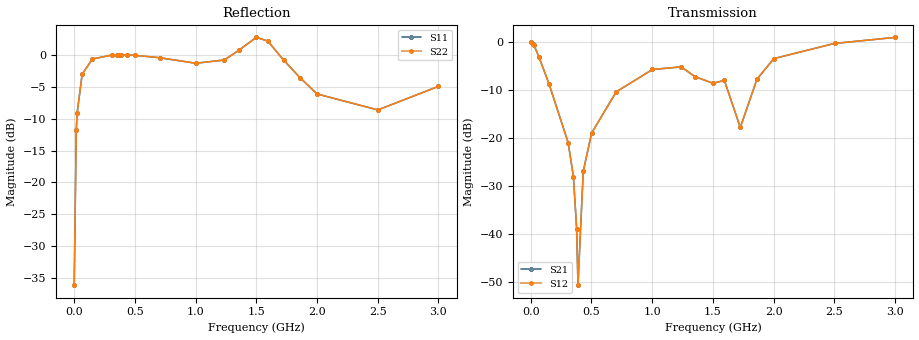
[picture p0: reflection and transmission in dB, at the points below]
!s-Parameter Generated by FASTRON Sdn. Bhd.
!FASTRON P/N : MICC-R27X
!Keysight Technologies,E4991B,MY54100416,A.01.15
!Date: Fri Aug 21 15:37:45 2026
!Version  : Rev00 Fri Aug 21 15:37:45 2026
!Data & Calibration Information:
!PortZ  Port1:50+j0  Port2:50+j0
!When reading, reference impedance value at option line is always used.
!Remarks : This data is being provided solely for informational purposes.
!Freq	S11	S21	S12	S22
# Hz S dB R 50
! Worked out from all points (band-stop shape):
!   1601 points, 1 MHz to 3 GHz, reference 50 ohm
!   highest |S21| = 0.92 dB at 3 GHz (marker M1); lowest = -50.6 dB at 389 MHz (marker M2)
!   |S21| within 3 dB of the highest: start of sweep to 51.23 MHz; 2.117 GHz to end of sweep
!   lowest |S11| = -36.1 dB at 1 MHz (marker M3), VSWR 1.03, Z = 50.2 + j1.57 ohm
!   |S11| at or under -10 dB: start of sweep to 22.54 MHz
!   |S22| runs from -36.1 to 2.8 dB; largest |S21 - S12| = 0
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1000000  -36.07 83.3  -0.01 -0.9  -0.01 -0.9  -36.07 83.3
1.786938e7  -11.82 73.6  -0.36 -14.9  -0.36 -14.9  -11.82 73.6
2.536688e7  -9.09 68.2  -0.64 -20.6  -0.64 -20.6  -9.09 68.2
6.660312e7  -3.05 44.4  -3.10 -44.8  -3.10 -44.8  -3.05 44.4
1.5095e8  -0.66 21.3  -8.79 -68.0  -8.79 -68.0  -0.66 21.3
3.083975e8  -0.06 5.1  -21.02 -83.1  -21.02 -83.1  -0.06 5.1
3.515081e8  -0.03 2.2  -28.13 -83.8  -28.13 -83.8  -0.03 2.2
3.777494e8  -0.03 0.6  -38.85 -75.0  -38.85 -75.0  -0.03 0.6
3.889956e8  -0.02 -0.0  -50.63 14.6  -50.63 14.6  -0.02 -0.0
4.321062e8  -0.03 -2.6  -26.97 83.9  -26.97 83.9  -0.03 -2.6
5.014581e8  -0.09 -6.5  -18.98 81.8  -18.98 81.8  -0.09 -6.5
7.038906e8  -0.46 -17.5  -10.41 71.5  -10.41 71.5  -0.46 -17.5
1.001916e9  -1.33 -31.0  -5.76 59.1  -5.76 59.1  -1.33 -31.0
1.238088e9  -0.82 -32.9  -5.22 64.5  -5.22 64.5  -0.82 -32.9
1.354299e9  0.67 -23.6  -7.27 88.6  -7.27 88.6  0.67 -23.6
1.5005e9  2.72 2.4  -8.63 -171.1  -8.63 -171.1  2.72 2.4
1.594219e9  2.15 14.2  -8.03 -127.6  -8.03 -127.6  2.15 14.2
1.725425e9  -0.84 5.4  -17.83 -41.5  -17.83 -41.5  -0.84 5.4
1.862254e9  -3.63 -15.8  -7.79 26.1  -7.79 26.1  -3.63 -15.8
2.000958e9  -6.14 -36.1  -3.50 25.8  -3.50 25.8  -6.14 -36.1
2.501416e9  -8.64 -73.4  -0.34 21.6  -0.34 21.6  -8.64 -73.4
3e9  -4.95 -85.7  0.92 30.5  0.92 30.5  -4.95 -85.7
